VERSION 5.7 ;
  DIVIDERCHAR "/" ;
  BUSBITCHARS "[]" ;
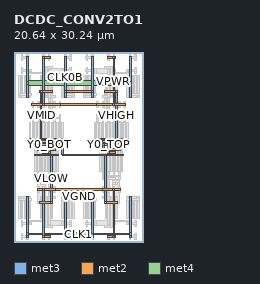
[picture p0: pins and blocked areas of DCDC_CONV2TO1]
MACRO DCDC_CONV2TO1
  CLASS BLOCK ;
  ORIGIN 0 0 ;
  FOREIGN DCDC_CONV2TO1 0 0 ;
  SIZE 20.64 BY 30.24 ;
  PIN CLK0
    DIRECTION INOUT ;
    USE SIGNAL ;
    PORT
      LAYER met3 ;
        RECT 18.35 0.68 18.63 7.3 ;
      LAYER met3 ;
        RECT 2.01 0.68 2.29 7.3 ;
      LAYER met3 ;
        RECT 18.35 1.075 18.63 1.445 ;
      LAYER met2 ;
        RECT 2.15 1.12 18.49 1.4 ;
      LAYER met3 ;
        RECT 2.01 1.075 2.29 1.445 ;
    END
  END CLK0
  PIN CLK0B
    DIRECTION INOUT ;
    USE SIGNAL ;
    PORT
      LAYER met3 ;
        RECT 12.33 22.94 12.61 29.56 ;
      LAYER met3 ;
        RECT 8.03 22.94 8.31 29.56 ;
      LAYER met3 ;
        RECT 12.33 23.755 12.61 24.125 ;
      LAYER met2 ;
        RECT 8.17 23.8 12.47 24.08 ;
      LAYER met3 ;
        RECT 8.03 23.755 8.31 24.125 ;
    END
  END CLK0B
  PIN CLK1
    DIRECTION INOUT ;
    USE SIGNAL ;
    PORT
      LAYER met3 ;
        RECT 12.33 0.68 12.61 7.3 ;
      LAYER met3 ;
        RECT 8.03 0.68 8.31 7.3 ;
      LAYER met3 ;
        RECT 12.33 0.915 12.61 1.285 ;
      LAYER met4 ;
        RECT 8.17 0.7 12.47 1.5 ;
      LAYER met3 ;
        RECT 8.03 0.915 8.31 1.285 ;
    END
  END CLK1
  PIN CLK1B
    DIRECTION INOUT ;
    USE SIGNAL ;
    PORT
      LAYER met3 ;
        RECT 18.35 22.94 18.63 29.56 ;
      LAYER met3 ;
        RECT 2.01 22.94 2.29 29.56 ;
      LAYER met3 ;
        RECT 18.35 25.115 18.63 25.485 ;
      LAYER met4 ;
        RECT 2.15 24.9 18.49 25.7 ;
      LAYER met3 ;
        RECT 2.01 25.115 2.29 25.485 ;
    END
  END CLK1B
  PIN VGND
    DIRECTION INOUT ;
    USE SIGNAL ;
    PORT
      LAYER met2 ;
        RECT 14.88 0.7 16.08 0.98 ;
      LAYER met2 ;
        RECT 14.02 8.26 16.94 8.54 ;
      LAYER met2 ;
        RECT 15.75 0.7 16.07 0.98 ;
      LAYER met3 ;
        RECT 15.77 0.84 16.05 8.4 ;
      LAYER met2 ;
        RECT 15.75 8.26 16.07 8.54 ;
      LAYER met2 ;
        RECT 4.56 0.7 5.76 0.98 ;
      LAYER met2 ;
        RECT 3.7 8.26 6.62 8.54 ;
      LAYER met2 ;
        RECT 4.57 0.7 4.89 0.98 ;
      LAYER met3 ;
        RECT 4.59 0.84 4.87 8.4 ;
      LAYER met2 ;
        RECT 4.57 8.26 4.89 8.54 ;
      LAYER met2 ;
        RECT 6.45 8.26 14.19 8.54 ;
    END
  END VGND
  PIN VHIGH
    DIRECTION INOUT ;
    USE SIGNAL ;
    PORT
      LAYER met2 ;
        RECT 14.45 23.8 16.51 24.08 ;
      LAYER met2 ;
        RECT 12.73 16.24 18.23 16.52 ;
      LAYER met2 ;
        RECT 16.18 23.8 16.5 24.08 ;
      LAYER met3 ;
        RECT 16.2 16.38 16.48 23.94 ;
      LAYER met2 ;
        RECT 16.18 16.24 16.5 16.52 ;
    END
  END VHIGH
  PIN VLOW
    DIRECTION INOUT ;
    USE SIGNAL ;
    PORT
      LAYER met2 ;
        RECT 4.13 6.16 6.19 6.44 ;
      LAYER met2 ;
        RECT 3.27 13.72 7.05 14 ;
      LAYER met2 ;
        RECT 5.86 6.16 6.18 6.44 ;
      LAYER met3 ;
        RECT 5.88 6.3 6.16 13.86 ;
      LAYER met2 ;
        RECT 5.86 13.72 6.18 14 ;
    END
  END VLOW
  PIN VMID
    DIRECTION INOUT ;
    USE SIGNAL ;
    PORT
      LAYER met2 ;
        RECT 14.45 6.16 16.51 6.44 ;
      LAYER met2 ;
        RECT 13.59 13.72 17.37 14 ;
      LAYER met2 ;
        RECT 14.46 6.16 14.78 6.44 ;
      LAYER met3 ;
        RECT 14.48 6.3 14.76 13.86 ;
      LAYER met2 ;
        RECT 14.46 13.72 14.78 14 ;
      LAYER met2 ;
        RECT 4.13 23.8 6.19 24.08 ;
      LAYER met2 ;
        RECT 2.41 16.24 7.91 16.52 ;
      LAYER met2 ;
        RECT 4.14 23.8 4.46 24.08 ;
      LAYER met3 ;
        RECT 4.16 16.38 4.44 23.94 ;
      LAYER met2 ;
        RECT 4.14 16.24 4.46 16.52 ;
      LAYER met2 ;
        RECT 7.74 13.72 13.76 14 ;
      LAYER met3 ;
        RECT 7.6 13.86 7.88 16.38 ;
      LAYER met2 ;
        RECT 7.58 16.24 7.9 16.52 ;
    END
  END VMID
  PIN VPWR
    DIRECTION INOUT ;
    USE SIGNAL ;
    PORT
      LAYER met2 ;
        RECT 14.88 29.26 16.08 29.54 ;
      LAYER met2 ;
        RECT 13.16 21.7 17.8 21.98 ;
      LAYER met2 ;
        RECT 15.75 29.26 16.07 29.54 ;
      LAYER met3 ;
        RECT 15.77 21.84 16.05 29.4 ;
      LAYER met2 ;
        RECT 15.75 21.7 16.07 21.98 ;
      LAYER met2 ;
        RECT 4.56 29.26 5.76 29.54 ;
      LAYER met2 ;
        RECT 2.84 21.7 7.48 21.98 ;
      LAYER met2 ;
        RECT 4.57 29.26 4.89 29.54 ;
      LAYER met3 ;
        RECT 4.59 21.84 4.87 29.4 ;
      LAYER met2 ;
        RECT 4.57 21.7 4.89 21.98 ;
      LAYER met2 ;
        RECT 7.31 21.7 13.33 21.98 ;
    END
  END VPWR
  PIN Y0_BOT
    DIRECTION INOUT ;
    USE SIGNAL ;
    PORT
      LAYER met2 ;
        RECT 3.7 15.4 7.48 15.68 ;
      LAYER met2 ;
        RECT 3.7 14.56 6.62 14.84 ;
      LAYER met2 ;
        RECT 6.29 15.4 6.61 15.68 ;
      LAYER met3 ;
        RECT 6.31 14.7 6.59 15.54 ;
      LAYER met2 ;
        RECT 6.29 14.56 6.61 14.84 ;
    END
  END Y0_BOT
  PIN Y0_TOP
    DIRECTION INOUT ;
    USE SIGNAL ;
    PORT
      LAYER met2 ;
        RECT 13.16 15.4 16.94 15.68 ;
      LAYER met2 ;
        RECT 14.02 14.56 16.94 14.84 ;
      LAYER met2 ;
        RECT 14.03 15.4 14.35 15.68 ;
      LAYER met3 ;
        RECT 14.05 14.7 14.33 15.54 ;
      LAYER met2 ;
        RECT 14.03 14.56 14.35 14.84 ;
    END
  END Y0_TOP
  PIN Y1_BOT
    DIRECTION INOUT ;
    USE SIGNAL ;
    PORT
      LAYER met2 ;
        RECT 2.84 15.82 6.62 16.1 ;
      LAYER met2 ;
        RECT 4.56 14.14 5.76 14.42 ;
      LAYER met2 ;
        RECT 5.43 15.82 5.75 16.1 ;
      LAYER met3 ;
        RECT 5.45 14.28 5.73 15.96 ;
      LAYER met2 ;
        RECT 5.43 14.14 5.75 14.42 ;
    END
  END Y1_BOT
  PIN Y1_TOP
    DIRECTION INOUT ;
    USE SIGNAL ;
    PORT
      LAYER met2 ;
        RECT 14.02 15.82 17.8 16.1 ;
      LAYER met2 ;
        RECT 14.88 14.14 16.08 14.42 ;
      LAYER met2 ;
        RECT 14.89 15.82 15.21 16.1 ;
      LAYER met3 ;
        RECT 14.91 14.28 15.19 15.96 ;
      LAYER met2 ;
        RECT 14.89 14.14 15.21 14.42 ;
    END
  END Y1_TOP
  OBS
  LAYER met3 ;
        RECT 14.91 22.94 15.19 27.46 ;
  LAYER met2 ;
        RECT 13.16 19.6 16.94 19.88 ;
  LAYER met2 ;
        RECT 11.44 27.16 12.64 27.44 ;
  LAYER met3 ;
        RECT 14.91 19.74 15.19 23.1 ;
  LAYER met2 ;
        RECT 14.89 19.6 15.21 19.88 ;
  LAYER met3 ;
        RECT 14.91 27.035 15.19 27.405 ;
  LAYER met4 ;
        RECT 12.9 26.82 15.05 27.62 ;
  LAYER met3 ;
        RECT 12.76 27.139 13.04 27.381 ;
  LAYER met2 ;
        RECT 12.47 27.16 12.9 27.44 ;
  LAYER met2 ;
        RECT 14.89 19.6 15.21 19.88 ;
  LAYER met3 ;
        RECT 14.91 19.58 15.19 19.9 ;
  LAYER met2 ;
        RECT 12.74 27.16 13.06 27.44 ;
  LAYER met3 ;
        RECT 12.76 27.14 13.04 27.46 ;
  LAYER met2 ;
        RECT 14.89 19.6 15.21 19.88 ;
  LAYER met3 ;
        RECT 14.91 19.58 15.19 19.9 ;
  LAYER met3 ;
        RECT 12.76 27.035 13.04 27.405 ;
  LAYER met4 ;
        RECT 12.735 26.82 13.065 27.62 ;
  LAYER met3 ;
        RECT 14.91 27.035 15.19 27.405 ;
  LAYER met4 ;
        RECT 14.885 26.82 15.215 27.62 ;
  LAYER met2 ;
        RECT 14.89 19.6 15.21 19.88 ;
  LAYER met3 ;
        RECT 14.91 19.58 15.19 19.9 ;
  LAYER met3 ;
        RECT 14.91 27.035 15.19 27.405 ;
  LAYER met4 ;
        RECT 14.885 26.82 15.215 27.62 ;
  LAYER met3 ;
        RECT 15.34 23.36 15.62 27.88 ;
  LAYER met2 ;
        RECT 14.02 20.02 17.8 20.3 ;
  LAYER met2 ;
        RECT 18.32 27.16 19.52 27.44 ;
  LAYER met3 ;
        RECT 15.34 23.735 15.62 24.105 ;
  LAYER met4 ;
        RECT 14.62 23.52 15.48 24.32 ;
  LAYER met3 ;
        RECT 14.48 20.16 14.76 23.92 ;
  LAYER met2 ;
        RECT 14.46 20.02 14.78 20.3 ;
  LAYER met3 ;
        RECT 15.34 26.695 15.62 27.065 ;
  LAYER met2 ;
        RECT 15.48 26.74 18.06 27.02 ;
  LAYER met1 ;
        RECT 17.935 26.88 18.185 27.3 ;
  LAYER met2 ;
        RECT 18.06 27.16 18.49 27.44 ;
  LAYER met2 ;
        RECT 14.46 20.02 14.78 20.3 ;
  LAYER met3 ;
        RECT 14.48 20 14.76 20.32 ;
  LAYER met3 ;
        RECT 14.48 23.735 14.76 24.105 ;
  LAYER met4 ;
        RECT 14.455 23.52 14.785 24.32 ;
  LAYER met3 ;
        RECT 15.34 23.735 15.62 24.105 ;
  LAYER met4 ;
        RECT 15.315 23.52 15.645 24.32 ;
  LAYER met1 ;
        RECT 17.935 26.795 18.185 26.965 ;
  LAYER met2 ;
        RECT 17.89 26.74 18.23 27.02 ;
  LAYER met1 ;
        RECT 17.935 27.215 18.185 27.385 ;
  LAYER met2 ;
        RECT 17.89 27.16 18.23 27.44 ;
  LAYER met2 ;
        RECT 14.46 20.02 14.78 20.3 ;
  LAYER met3 ;
        RECT 14.48 20 14.76 20.32 ;
  LAYER met2 ;
        RECT 15.32 26.74 15.64 27.02 ;
  LAYER met3 ;
        RECT 15.34 26.72 15.62 27.04 ;
  LAYER met3 ;
        RECT 14.48 23.735 14.76 24.105 ;
  LAYER met4 ;
        RECT 14.455 23.52 14.785 24.32 ;
  LAYER met3 ;
        RECT 15.34 23.735 15.62 24.105 ;
  LAYER met4 ;
        RECT 15.315 23.52 15.645 24.32 ;
  LAYER met1 ;
        RECT 17.935 26.795 18.185 26.965 ;
  LAYER met2 ;
        RECT 17.89 26.74 18.23 27.02 ;
  LAYER met1 ;
        RECT 17.935 27.215 18.185 27.385 ;
  LAYER met2 ;
        RECT 17.89 27.16 18.23 27.44 ;
  LAYER met2 ;
        RECT 14.46 20.02 14.78 20.3 ;
  LAYER met3 ;
        RECT 14.48 20 14.76 20.32 ;
  LAYER met2 ;
        RECT 15.32 26.74 15.64 27.02 ;
  LAYER met3 ;
        RECT 15.34 26.72 15.62 27.04 ;
  LAYER met3 ;
        RECT 14.48 23.735 14.76 24.105 ;
  LAYER met4 ;
        RECT 14.455 23.52 14.785 24.32 ;
  LAYER met3 ;
        RECT 15.34 23.735 15.62 24.105 ;
  LAYER met4 ;
        RECT 15.315 23.52 15.645 24.32 ;
  LAYER met1 ;
        RECT 14.925 23.015 15.175 26.545 ;
  LAYER met1 ;
        RECT 14.925 26.795 15.175 27.805 ;
  LAYER met1 ;
        RECT 14.925 28.895 15.175 29.905 ;
  LAYER met1 ;
        RECT 14.495 23.015 14.745 26.545 ;
  LAYER met1 ;
        RECT 15.355 23.015 15.605 26.545 ;
  LAYER met1 ;
        RECT 15.785 23.015 16.035 26.545 ;
  LAYER met1 ;
        RECT 15.785 26.795 16.035 27.805 ;
  LAYER met1 ;
        RECT 15.785 28.895 16.035 29.905 ;
  LAYER met1 ;
        RECT 16.215 23.015 16.465 26.545 ;
  LAYER met2 ;
        RECT 14.88 27.16 16.08 27.44 ;
  LAYER met2 ;
        RECT 14.02 22.96 15.22 23.24 ;
  LAYER met2 ;
        RECT 14.45 27.58 15.65 27.86 ;
  LAYER met2 ;
        RECT 14.88 23.38 16.08 23.66 ;
  LAYER met2 ;
        RECT 14.88 29.26 16.08 29.54 ;
  LAYER met3 ;
        RECT 14.91 22.94 15.19 27.46 ;
  LAYER met3 ;
        RECT 15.34 23.36 15.62 27.88 ;
  LAYER met2 ;
        RECT 14.45 23.8 16.51 24.08 ;
  LAYER met1 ;
        RECT 13.205 15.455 13.455 18.985 ;
  LAYER met1 ;
        RECT 13.205 19.235 13.455 20.245 ;
  LAYER met1 ;
        RECT 13.205 21.335 13.455 22.345 ;
  LAYER met1 ;
        RECT 12.775 15.455 13.025 18.985 ;
  LAYER met1 ;
        RECT 13.635 15.455 13.885 18.985 ;
  LAYER met1 ;
        RECT 14.065 15.455 14.315 18.985 ;
  LAYER met1 ;
        RECT 14.065 19.235 14.315 20.245 ;
  LAYER met1 ;
        RECT 14.065 21.335 14.315 22.345 ;
  LAYER met1 ;
        RECT 14.495 15.455 14.745 18.985 ;
  LAYER met1 ;
        RECT 14.925 15.455 15.175 18.985 ;
  LAYER met1 ;
        RECT 14.925 19.235 15.175 20.245 ;
  LAYER met1 ;
        RECT 14.925 21.335 15.175 22.345 ;
  LAYER met1 ;
        RECT 15.355 15.455 15.605 18.985 ;
  LAYER met1 ;
        RECT 15.785 15.455 16.035 18.985 ;
  LAYER met1 ;
        RECT 15.785 19.235 16.035 20.245 ;
  LAYER met1 ;
        RECT 15.785 21.335 16.035 22.345 ;
  LAYER met1 ;
        RECT 16.215 15.455 16.465 18.985 ;
  LAYER met1 ;
        RECT 16.645 15.455 16.895 18.985 ;
  LAYER met1 ;
        RECT 16.645 19.235 16.895 20.245 ;
  LAYER met1 ;
        RECT 16.645 21.335 16.895 22.345 ;
  LAYER met1 ;
        RECT 17.075 15.455 17.325 18.985 ;
  LAYER met1 ;
        RECT 17.505 15.455 17.755 18.985 ;
  LAYER met1 ;
        RECT 17.505 19.235 17.755 20.245 ;
  LAYER met1 ;
        RECT 17.505 21.335 17.755 22.345 ;
  LAYER met1 ;
        RECT 17.935 15.455 18.185 18.985 ;
  LAYER met2 ;
        RECT 13.16 21.7 17.8 21.98 ;
  LAYER met2 ;
        RECT 13.16 15.4 16.94 15.68 ;
  LAYER met2 ;
        RECT 14.02 15.82 17.8 16.1 ;
  LAYER met2 ;
        RECT 13.16 19.6 16.94 19.88 ;
  LAYER met2 ;
        RECT 14.02 20.02 17.8 20.3 ;
  LAYER met2 ;
        RECT 12.73 16.24 18.23 16.52 ;
  LAYER met1 ;
        RECT 11.485 23.015 11.735 26.545 ;
  LAYER met1 ;
        RECT 11.485 26.795 11.735 27.805 ;
  LAYER met1 ;
        RECT 11.485 28.895 11.735 29.905 ;
  LAYER met1 ;
        RECT 11.055 23.015 11.305 26.545 ;
  LAYER met1 ;
        RECT 11.915 23.015 12.165 26.545 ;
  LAYER met1 ;
        RECT 12.345 23.015 12.595 26.545 ;
  LAYER met1 ;
        RECT 12.345 26.795 12.595 27.805 ;
  LAYER met1 ;
        RECT 12.345 28.895 12.595 29.905 ;
  LAYER met1 ;
        RECT 12.775 23.015 13.025 26.545 ;
  LAYER met2 ;
        RECT 11.44 29.26 12.64 29.54 ;
  LAYER met2 ;
        RECT 11.44 22.96 12.64 23.24 ;
  LAYER met2 ;
        RECT 11.01 23.38 13.07 23.66 ;
  LAYER met2 ;
        RECT 11.44 27.16 12.64 27.44 ;
  LAYER met3 ;
        RECT 12.33 22.94 12.61 29.56 ;
  LAYER met1 ;
        RECT 19.225 23.015 19.475 26.545 ;
  LAYER met1 ;
        RECT 19.225 26.795 19.475 27.805 ;
  LAYER met1 ;
        RECT 19.225 28.895 19.475 29.905 ;
  LAYER met1 ;
        RECT 19.655 23.015 19.905 26.545 ;
  LAYER met1 ;
        RECT 18.795 23.015 19.045 26.545 ;
  LAYER met1 ;
        RECT 18.365 23.015 18.615 26.545 ;
  LAYER met1 ;
        RECT 18.365 26.795 18.615 27.805 ;
  LAYER met1 ;
        RECT 18.365 28.895 18.615 29.905 ;
  LAYER met1 ;
        RECT 17.935 23.015 18.185 26.545 ;
  LAYER met2 ;
        RECT 18.32 29.26 19.52 29.54 ;
  LAYER met2 ;
        RECT 18.32 22.96 19.52 23.24 ;
  LAYER met2 ;
        RECT 17.89 23.38 19.95 23.66 ;
  LAYER met2 ;
        RECT 18.32 27.16 19.52 27.44 ;
  LAYER met3 ;
        RECT 18.35 22.94 18.63 29.56 ;
  LAYER met3 ;
        RECT 14.91 2.78 15.19 7.3 ;
  LAYER met2 ;
        RECT 14.02 10.36 16.94 10.64 ;
  LAYER met2 ;
        RECT 11.44 2.8 12.64 3.08 ;
  LAYER met3 ;
        RECT 14.91 7.14 15.19 10.5 ;
  LAYER met2 ;
        RECT 14.89 10.36 15.21 10.64 ;
  LAYER met3 ;
        RECT 14.91 2.835 15.19 3.205 ;
  LAYER met4 ;
        RECT 12.9 2.62 15.05 3.42 ;
  LAYER met3 ;
        RECT 12.76 2.859 13.04 3.101 ;
  LAYER met2 ;
        RECT 12.47 2.8 12.9 3.08 ;
  LAYER met2 ;
        RECT 14.89 10.36 15.21 10.64 ;
  LAYER met3 ;
        RECT 14.91 10.34 15.19 10.66 ;
  LAYER met2 ;
        RECT 12.74 2.8 13.06 3.08 ;
  LAYER met3 ;
        RECT 12.76 2.78 13.04 3.1 ;
  LAYER met2 ;
        RECT 14.89 10.36 15.21 10.64 ;
  LAYER met3 ;
        RECT 14.91 10.34 15.19 10.66 ;
  LAYER met3 ;
        RECT 12.76 2.835 13.04 3.205 ;
  LAYER met4 ;
        RECT 12.735 2.62 13.065 3.42 ;
  LAYER met3 ;
        RECT 14.91 2.835 15.19 3.205 ;
  LAYER met4 ;
        RECT 14.885 2.62 15.215 3.42 ;
  LAYER met2 ;
        RECT 14.89 10.36 15.21 10.64 ;
  LAYER met3 ;
        RECT 14.91 10.34 15.19 10.66 ;
  LAYER met3 ;
        RECT 14.91 2.835 15.19 3.205 ;
  LAYER met4 ;
        RECT 14.885 2.62 15.215 3.42 ;
  LAYER met3 ;
        RECT 15.34 2.36 15.62 6.88 ;
  LAYER met2 ;
        RECT 14.88 9.94 16.08 10.22 ;
  LAYER met2 ;
        RECT 18.32 2.8 19.52 3.08 ;
  LAYER met3 ;
        RECT 15.34 6.135 15.62 6.505 ;
  LAYER met4 ;
        RECT 15.48 5.92 16.24 6.72 ;
  LAYER met5 ;
        RECT 15.65 6.32 16.83 9.62 ;
  LAYER met4 ;
        RECT 15.91 9.22 16.24 10.02 ;
  LAYER met3 ;
        RECT 15.77 9.62 16.05 10.08 ;
  LAYER met2 ;
        RECT 15.75 9.94 16.07 10.22 ;
  LAYER met3 ;
        RECT 15.34 3.175 15.62 3.545 ;
  LAYER met2 ;
        RECT 15.48 3.22 18.06 3.5 ;
  LAYER met1 ;
        RECT 17.935 2.94 18.185 3.36 ;
  LAYER met2 ;
        RECT 18.06 2.8 18.49 3.08 ;
  LAYER met2 ;
        RECT 15.75 9.94 16.07 10.22 ;
  LAYER met3 ;
        RECT 15.77 9.92 16.05 10.24 ;
  LAYER met3 ;
        RECT 15.34 6.135 15.62 6.505 ;
  LAYER met4 ;
        RECT 15.315 5.92 15.645 6.72 ;
  LAYER met3 ;
        RECT 15.77 9.435 16.05 9.805 ;
  LAYER met4 ;
        RECT 15.745 9.22 16.075 10.02 ;
  LAYER met4 ;
        RECT 16.075 9.22 16.405 10.02 ;
  LAYER met5 ;
        RECT 15.65 9.455 16.83 9.785 ;
  LAYER met4 ;
        RECT 16.075 5.92 16.405 6.72 ;
  LAYER met5 ;
        RECT 15.65 6.155 16.83 6.485 ;
  LAYER met1 ;
        RECT 17.935 3.275 18.185 3.445 ;
  LAYER met2 ;
        RECT 17.89 3.22 18.23 3.5 ;
  LAYER met1 ;
        RECT 17.935 2.855 18.185 3.025 ;
  LAYER met2 ;
        RECT 17.89 2.8 18.23 3.08 ;
  LAYER met2 ;
        RECT 15.32 3.22 15.64 3.5 ;
  LAYER met3 ;
        RECT 15.34 3.2 15.62 3.52 ;
  LAYER met2 ;
        RECT 15.75 9.94 16.07 10.22 ;
  LAYER met3 ;
        RECT 15.77 9.92 16.05 10.24 ;
  LAYER met3 ;
        RECT 15.34 6.135 15.62 6.505 ;
  LAYER met4 ;
        RECT 15.315 5.92 15.645 6.72 ;
  LAYER met3 ;
        RECT 15.77 9.435 16.05 9.805 ;
  LAYER met4 ;
        RECT 15.745 9.22 16.075 10.02 ;
  LAYER met4 ;
        RECT 16.075 9.22 16.405 10.02 ;
  LAYER met5 ;
        RECT 15.65 9.455 16.83 9.785 ;
  LAYER met4 ;
        RECT 16.075 5.92 16.405 6.72 ;
  LAYER met5 ;
        RECT 15.65 6.155 16.83 6.485 ;
  LAYER met1 ;
        RECT 17.935 3.275 18.185 3.445 ;
  LAYER met2 ;
        RECT 17.89 3.22 18.23 3.5 ;
  LAYER met1 ;
        RECT 17.935 2.855 18.185 3.025 ;
  LAYER met2 ;
        RECT 17.89 2.8 18.23 3.08 ;
  LAYER met2 ;
        RECT 15.32 3.22 15.64 3.5 ;
  LAYER met3 ;
        RECT 15.34 3.2 15.62 3.52 ;
  LAYER met2 ;
        RECT 15.75 9.94 16.07 10.22 ;
  LAYER met3 ;
        RECT 15.77 9.92 16.05 10.24 ;
  LAYER met3 ;
        RECT 15.34 6.135 15.62 6.505 ;
  LAYER met4 ;
        RECT 15.315 5.92 15.645 6.72 ;
  LAYER met3 ;
        RECT 15.77 9.435 16.05 9.805 ;
  LAYER met4 ;
        RECT 15.745 9.22 16.075 10.02 ;
  LAYER met4 ;
        RECT 16.075 9.22 16.405 10.02 ;
  LAYER met5 ;
        RECT 15.65 9.455 16.83 9.785 ;
  LAYER met4 ;
        RECT 16.075 5.92 16.405 6.72 ;
  LAYER met5 ;
        RECT 15.65 6.155 16.83 6.485 ;
  LAYER met1 ;
        RECT 14.925 3.695 15.175 7.225 ;
  LAYER met1 ;
        RECT 14.925 2.435 15.175 3.445 ;
  LAYER met1 ;
        RECT 14.925 0.335 15.175 1.345 ;
  LAYER met1 ;
        RECT 14.495 3.695 14.745 7.225 ;
  LAYER met1 ;
        RECT 15.355 3.695 15.605 7.225 ;
  LAYER met1 ;
        RECT 15.785 3.695 16.035 7.225 ;
  LAYER met1 ;
        RECT 15.785 2.435 16.035 3.445 ;
  LAYER met1 ;
        RECT 15.785 0.335 16.035 1.345 ;
  LAYER met1 ;
        RECT 16.215 3.695 16.465 7.225 ;
  LAYER met2 ;
        RECT 14.88 2.8 16.08 3.08 ;
  LAYER met2 ;
        RECT 14.02 7 15.22 7.28 ;
  LAYER met2 ;
        RECT 14.45 2.38 15.65 2.66 ;
  LAYER met2 ;
        RECT 14.88 6.58 16.08 6.86 ;
  LAYER met2 ;
        RECT 14.88 0.7 16.08 0.98 ;
  LAYER met3 ;
        RECT 14.91 2.78 15.19 7.3 ;
  LAYER met3 ;
        RECT 15.34 2.36 15.62 6.88 ;
  LAYER met2 ;
        RECT 14.45 6.16 16.51 6.44 ;
  LAYER met1 ;
        RECT 14.065 11.255 14.315 14.785 ;
  LAYER met1 ;
        RECT 14.065 9.995 14.315 11.005 ;
  LAYER met1 ;
        RECT 14.065 7.895 14.315 8.905 ;
  LAYER met1 ;
        RECT 13.635 11.255 13.885 14.785 ;
  LAYER met1 ;
        RECT 14.495 11.255 14.745 14.785 ;
  LAYER met1 ;
        RECT 14.925 11.255 15.175 14.785 ;
  LAYER met1 ;
        RECT 14.925 9.995 15.175 11.005 ;
  LAYER met1 ;
        RECT 14.925 7.895 15.175 8.905 ;
  LAYER met1 ;
        RECT 15.355 11.255 15.605 14.785 ;
  LAYER met1 ;
        RECT 15.785 11.255 16.035 14.785 ;
  LAYER met1 ;
        RECT 15.785 9.995 16.035 11.005 ;
  LAYER met1 ;
        RECT 15.785 7.895 16.035 8.905 ;
  LAYER met1 ;
        RECT 16.215 11.255 16.465 14.785 ;
  LAYER met1 ;
        RECT 16.645 11.255 16.895 14.785 ;
  LAYER met1 ;
        RECT 16.645 9.995 16.895 11.005 ;
  LAYER met1 ;
        RECT 16.645 7.895 16.895 8.905 ;
  LAYER met1 ;
        RECT 17.075 11.255 17.325 14.785 ;
  LAYER met2 ;
        RECT 14.02 8.26 16.94 8.54 ;
  LAYER met2 ;
        RECT 14.02 14.56 16.94 14.84 ;
  LAYER met2 ;
        RECT 14.88 14.14 16.08 14.42 ;
  LAYER met2 ;
        RECT 14.02 10.36 16.94 10.64 ;
  LAYER met2 ;
        RECT 14.88 9.94 16.08 10.22 ;
  LAYER met2 ;
        RECT 13.59 13.72 17.37 14 ;
  LAYER met1 ;
        RECT 11.485 3.695 11.735 7.225 ;
  LAYER met1 ;
        RECT 11.485 2.435 11.735 3.445 ;
  LAYER met1 ;
        RECT 11.485 0.335 11.735 1.345 ;
  LAYER met1 ;
        RECT 11.055 3.695 11.305 7.225 ;
  LAYER met1 ;
        RECT 11.915 3.695 12.165 7.225 ;
  LAYER met1 ;
        RECT 12.345 3.695 12.595 7.225 ;
  LAYER met1 ;
        RECT 12.345 2.435 12.595 3.445 ;
  LAYER met1 ;
        RECT 12.345 0.335 12.595 1.345 ;
  LAYER met1 ;
        RECT 12.775 3.695 13.025 7.225 ;
  LAYER met2 ;
        RECT 11.44 0.7 12.64 0.98 ;
  LAYER met2 ;
        RECT 11.44 7 12.64 7.28 ;
  LAYER met2 ;
        RECT 11.01 6.58 13.07 6.86 ;
  LAYER met2 ;
        RECT 11.44 2.8 12.64 3.08 ;
  LAYER met3 ;
        RECT 12.33 0.68 12.61 7.3 ;
  LAYER met1 ;
        RECT 19.225 3.695 19.475 7.225 ;
  LAYER met1 ;
        RECT 19.225 2.435 19.475 3.445 ;
  LAYER met1 ;
        RECT 19.225 0.335 19.475 1.345 ;
  LAYER met1 ;
        RECT 19.655 3.695 19.905 7.225 ;
  LAYER met1 ;
        RECT 18.795 3.695 19.045 7.225 ;
  LAYER met1 ;
        RECT 18.365 3.695 18.615 7.225 ;
  LAYER met1 ;
        RECT 18.365 2.435 18.615 3.445 ;
  LAYER met1 ;
        RECT 18.365 0.335 18.615 1.345 ;
  LAYER met1 ;
        RECT 17.935 3.695 18.185 7.225 ;
  LAYER met2 ;
        RECT 18.32 0.7 19.52 0.98 ;
  LAYER met2 ;
        RECT 18.32 7 19.52 7.28 ;
  LAYER met2 ;
        RECT 17.89 6.58 19.95 6.86 ;
  LAYER met2 ;
        RECT 18.32 2.8 19.52 3.08 ;
  LAYER met3 ;
        RECT 18.35 0.68 18.63 7.3 ;
  LAYER met3 ;
        RECT 5.45 22.94 5.73 27.46 ;
  LAYER met2 ;
        RECT 3.7 19.6 7.48 19.88 ;
  LAYER met2 ;
        RECT 8 27.16 9.2 27.44 ;
  LAYER met3 ;
        RECT 5.45 19.74 5.73 23.1 ;
  LAYER met2 ;
        RECT 5.43 19.6 5.75 19.88 ;
  LAYER met3 ;
        RECT 5.45 27.035 5.73 27.405 ;
  LAYER met4 ;
        RECT 5.59 26.82 7.74 27.62 ;
  LAYER met3 ;
        RECT 7.6 27.139 7.88 27.381 ;
  LAYER met2 ;
        RECT 7.74 27.16 8.17 27.44 ;
  LAYER met2 ;
        RECT 5.43 19.6 5.75 19.88 ;
  LAYER met3 ;
        RECT 5.45 19.58 5.73 19.9 ;
  LAYER met2 ;
        RECT 7.58 27.16 7.9 27.44 ;
  LAYER met3 ;
        RECT 7.6 27.14 7.88 27.46 ;
  LAYER met2 ;
        RECT 5.43 19.6 5.75 19.88 ;
  LAYER met3 ;
        RECT 5.45 19.58 5.73 19.9 ;
  LAYER met3 ;
        RECT 7.6 27.035 7.88 27.405 ;
  LAYER met4 ;
        RECT 7.575 26.82 7.905 27.62 ;
  LAYER met3 ;
        RECT 5.45 27.035 5.73 27.405 ;
  LAYER met4 ;
        RECT 5.425 26.82 5.755 27.62 ;
  LAYER met2 ;
        RECT 5.43 19.6 5.75 19.88 ;
  LAYER met3 ;
        RECT 5.45 19.58 5.73 19.9 ;
  LAYER met3 ;
        RECT 5.45 27.035 5.73 27.405 ;
  LAYER met4 ;
        RECT 5.425 26.82 5.755 27.62 ;
  LAYER met3 ;
        RECT 5.02 23.36 5.3 27.88 ;
  LAYER met2 ;
        RECT 2.84 20.02 6.62 20.3 ;
  LAYER met2 ;
        RECT 1.12 27.16 2.32 27.44 ;
  LAYER met3 ;
        RECT 5.02 23.735 5.3 24.105 ;
  LAYER met4 ;
        RECT 5.16 23.52 6.02 24.32 ;
  LAYER met3 ;
        RECT 5.88 20.16 6.16 23.92 ;
  LAYER met2 ;
        RECT 5.86 20.02 6.18 20.3 ;
  LAYER met3 ;
        RECT 5.02 26.695 5.3 27.065 ;
  LAYER met2 ;
        RECT 2.58 26.74 5.16 27.02 ;
  LAYER met1 ;
        RECT 2.455 26.88 2.705 27.3 ;
  LAYER met2 ;
        RECT 2.15 27.16 2.58 27.44 ;
  LAYER met2 ;
        RECT 5.86 20.02 6.18 20.3 ;
  LAYER met3 ;
        RECT 5.88 20 6.16 20.32 ;
  LAYER met3 ;
        RECT 5.88 23.735 6.16 24.105 ;
  LAYER met4 ;
        RECT 5.855 23.52 6.185 24.32 ;
  LAYER met3 ;
        RECT 5.02 23.735 5.3 24.105 ;
  LAYER met4 ;
        RECT 4.995 23.52 5.325 24.32 ;
  LAYER met1 ;
        RECT 2.455 26.795 2.705 26.965 ;
  LAYER met2 ;
        RECT 2.41 26.74 2.75 27.02 ;
  LAYER met1 ;
        RECT 2.455 27.215 2.705 27.385 ;
  LAYER met2 ;
        RECT 2.41 27.16 2.75 27.44 ;
  LAYER met2 ;
        RECT 5.86 20.02 6.18 20.3 ;
  LAYER met3 ;
        RECT 5.88 20 6.16 20.32 ;
  LAYER met2 ;
        RECT 5 26.74 5.32 27.02 ;
  LAYER met3 ;
        RECT 5.02 26.72 5.3 27.04 ;
  LAYER met3 ;
        RECT 5.88 23.735 6.16 24.105 ;
  LAYER met4 ;
        RECT 5.855 23.52 6.185 24.32 ;
  LAYER met3 ;
        RECT 5.02 23.735 5.3 24.105 ;
  LAYER met4 ;
        RECT 4.995 23.52 5.325 24.32 ;
  LAYER met1 ;
        RECT 2.455 26.795 2.705 26.965 ;
  LAYER met2 ;
        RECT 2.41 26.74 2.75 27.02 ;
  LAYER met1 ;
        RECT 2.455 27.215 2.705 27.385 ;
  LAYER met2 ;
        RECT 2.41 27.16 2.75 27.44 ;
  LAYER met2 ;
        RECT 5.86 20.02 6.18 20.3 ;
  LAYER met3 ;
        RECT 5.88 20 6.16 20.32 ;
  LAYER met2 ;
        RECT 5 26.74 5.32 27.02 ;
  LAYER met3 ;
        RECT 5.02 26.72 5.3 27.04 ;
  LAYER met3 ;
        RECT 5.88 23.735 6.16 24.105 ;
  LAYER met4 ;
        RECT 5.855 23.52 6.185 24.32 ;
  LAYER met3 ;
        RECT 5.02 23.735 5.3 24.105 ;
  LAYER met4 ;
        RECT 4.995 23.52 5.325 24.32 ;
  LAYER met1 ;
        RECT 5.465 23.015 5.715 26.545 ;
  LAYER met1 ;
        RECT 5.465 26.795 5.715 27.805 ;
  LAYER met1 ;
        RECT 5.465 28.895 5.715 29.905 ;
  LAYER met1 ;
        RECT 5.895 23.015 6.145 26.545 ;
  LAYER met1 ;
        RECT 5.035 23.015 5.285 26.545 ;
  LAYER met1 ;
        RECT 4.605 23.015 4.855 26.545 ;
  LAYER met1 ;
        RECT 4.605 26.795 4.855 27.805 ;
  LAYER met1 ;
        RECT 4.605 28.895 4.855 29.905 ;
  LAYER met1 ;
        RECT 4.175 23.015 4.425 26.545 ;
  LAYER met2 ;
        RECT 4.56 27.16 5.76 27.44 ;
  LAYER met2 ;
        RECT 5.42 22.96 6.62 23.24 ;
  LAYER met2 ;
        RECT 4.99 27.58 6.19 27.86 ;
  LAYER met2 ;
        RECT 4.56 23.38 5.76 23.66 ;
  LAYER met2 ;
        RECT 4.56 29.26 5.76 29.54 ;
  LAYER met3 ;
        RECT 5.45 22.94 5.73 27.46 ;
  LAYER met3 ;
        RECT 5.02 23.36 5.3 27.88 ;
  LAYER met2 ;
        RECT 4.13 23.8 6.19 24.08 ;
  LAYER met1 ;
        RECT 7.185 15.455 7.435 18.985 ;
  LAYER met1 ;
        RECT 7.185 19.235 7.435 20.245 ;
  LAYER met1 ;
        RECT 7.185 21.335 7.435 22.345 ;
  LAYER met1 ;
        RECT 7.615 15.455 7.865 18.985 ;
  LAYER met1 ;
        RECT 6.755 15.455 7.005 18.985 ;
  LAYER met1 ;
        RECT 6.325 15.455 6.575 18.985 ;
  LAYER met1 ;
        RECT 6.325 19.235 6.575 20.245 ;
  LAYER met1 ;
        RECT 6.325 21.335 6.575 22.345 ;
  LAYER met1 ;
        RECT 5.895 15.455 6.145 18.985 ;
  LAYER met1 ;
        RECT 5.465 15.455 5.715 18.985 ;
  LAYER met1 ;
        RECT 5.465 19.235 5.715 20.245 ;
  LAYER met1 ;
        RECT 5.465 21.335 5.715 22.345 ;
  LAYER met1 ;
        RECT 5.035 15.455 5.285 18.985 ;
  LAYER met1 ;
        RECT 4.605 15.455 4.855 18.985 ;
  LAYER met1 ;
        RECT 4.605 19.235 4.855 20.245 ;
  LAYER met1 ;
        RECT 4.605 21.335 4.855 22.345 ;
  LAYER met1 ;
        RECT 4.175 15.455 4.425 18.985 ;
  LAYER met1 ;
        RECT 3.745 15.455 3.995 18.985 ;
  LAYER met1 ;
        RECT 3.745 19.235 3.995 20.245 ;
  LAYER met1 ;
        RECT 3.745 21.335 3.995 22.345 ;
  LAYER met1 ;
        RECT 3.315 15.455 3.565 18.985 ;
  LAYER met1 ;
        RECT 2.885 15.455 3.135 18.985 ;
  LAYER met1 ;
        RECT 2.885 19.235 3.135 20.245 ;
  LAYER met1 ;
        RECT 2.885 21.335 3.135 22.345 ;
  LAYER met1 ;
        RECT 2.455 15.455 2.705 18.985 ;
  LAYER met2 ;
        RECT 2.84 21.7 7.48 21.98 ;
  LAYER met2 ;
        RECT 3.7 15.4 7.48 15.68 ;
  LAYER met2 ;
        RECT 2.84 15.82 6.62 16.1 ;
  LAYER met2 ;
        RECT 3.7 19.6 7.48 19.88 ;
  LAYER met2 ;
        RECT 2.84 20.02 6.62 20.3 ;
  LAYER met2 ;
        RECT 2.41 16.24 7.91 16.52 ;
  LAYER met1 ;
        RECT 8.905 23.015 9.155 26.545 ;
  LAYER met1 ;
        RECT 8.905 26.795 9.155 27.805 ;
  LAYER met1 ;
        RECT 8.905 28.895 9.155 29.905 ;
  LAYER met1 ;
        RECT 9.335 23.015 9.585 26.545 ;
  LAYER met1 ;
        RECT 8.475 23.015 8.725 26.545 ;
  LAYER met1 ;
        RECT 8.045 23.015 8.295 26.545 ;
  LAYER met1 ;
        RECT 8.045 26.795 8.295 27.805 ;
  LAYER met1 ;
        RECT 8.045 28.895 8.295 29.905 ;
  LAYER met1 ;
        RECT 7.615 23.015 7.865 26.545 ;
  LAYER met2 ;
        RECT 8 29.26 9.2 29.54 ;
  LAYER met2 ;
        RECT 8 22.96 9.2 23.24 ;
  LAYER met2 ;
        RECT 7.57 23.38 9.63 23.66 ;
  LAYER met2 ;
        RECT 8 27.16 9.2 27.44 ;
  LAYER met3 ;
        RECT 8.03 22.94 8.31 29.56 ;
  LAYER met1 ;
        RECT 1.165 23.015 1.415 26.545 ;
  LAYER met1 ;
        RECT 1.165 26.795 1.415 27.805 ;
  LAYER met1 ;
        RECT 1.165 28.895 1.415 29.905 ;
  LAYER met1 ;
        RECT 0.735 23.015 0.985 26.545 ;
  LAYER met1 ;
        RECT 1.595 23.015 1.845 26.545 ;
  LAYER met1 ;
        RECT 2.025 23.015 2.275 26.545 ;
  LAYER met1 ;
        RECT 2.025 26.795 2.275 27.805 ;
  LAYER met1 ;
        RECT 2.025 28.895 2.275 29.905 ;
  LAYER met1 ;
        RECT 2.455 23.015 2.705 26.545 ;
  LAYER met2 ;
        RECT 1.12 29.26 2.32 29.54 ;
  LAYER met2 ;
        RECT 1.12 22.96 2.32 23.24 ;
  LAYER met2 ;
        RECT 0.69 23.38 2.75 23.66 ;
  LAYER met2 ;
        RECT 1.12 27.16 2.32 27.44 ;
  LAYER met3 ;
        RECT 2.01 22.94 2.29 29.56 ;
  LAYER met3 ;
        RECT 5.45 2.78 5.73 7.3 ;
  LAYER met2 ;
        RECT 3.7 10.36 6.62 10.64 ;
  LAYER met2 ;
        RECT 8 2.8 9.2 3.08 ;
  LAYER met3 ;
        RECT 5.45 7.14 5.73 10.5 ;
  LAYER met2 ;
        RECT 5.43 10.36 5.75 10.64 ;
  LAYER met3 ;
        RECT 5.45 2.835 5.73 3.205 ;
  LAYER met4 ;
        RECT 5.59 2.62 7.74 3.42 ;
  LAYER met3 ;
        RECT 7.6 2.859 7.88 3.101 ;
  LAYER met2 ;
        RECT 7.74 2.8 8.17 3.08 ;
  LAYER met2 ;
        RECT 5.43 10.36 5.75 10.64 ;
  LAYER met3 ;
        RECT 5.45 10.34 5.73 10.66 ;
  LAYER met2 ;
        RECT 7.58 2.8 7.9 3.08 ;
  LAYER met3 ;
        RECT 7.6 2.78 7.88 3.1 ;
  LAYER met2 ;
        RECT 5.43 10.36 5.75 10.64 ;
  LAYER met3 ;
        RECT 5.45 10.34 5.73 10.66 ;
  LAYER met3 ;
        RECT 7.6 2.835 7.88 3.205 ;
  LAYER met4 ;
        RECT 7.575 2.62 7.905 3.42 ;
  LAYER met3 ;
        RECT 5.45 2.835 5.73 3.205 ;
  LAYER met4 ;
        RECT 5.425 2.62 5.755 3.42 ;
  LAYER met2 ;
        RECT 5.43 10.36 5.75 10.64 ;
  LAYER met3 ;
        RECT 5.45 10.34 5.73 10.66 ;
  LAYER met3 ;
        RECT 5.45 2.835 5.73 3.205 ;
  LAYER met4 ;
        RECT 5.425 2.62 5.755 3.42 ;
  LAYER met3 ;
        RECT 5.02 2.36 5.3 6.88 ;
  LAYER met2 ;
        RECT 4.56 9.94 5.76 10.22 ;
  LAYER met2 ;
        RECT 1.12 2.8 2.32 3.08 ;
  LAYER met3 ;
        RECT 5.02 6.135 5.3 6.505 ;
  LAYER met4 ;
        RECT 4.4 5.92 5.16 6.72 ;
  LAYER met5 ;
        RECT 3.81 6.32 4.99 9.62 ;
  LAYER met4 ;
        RECT 4.4 9.22 4.73 10.02 ;
  LAYER met3 ;
        RECT 4.59 9.62 4.87 10.08 ;
  LAYER met2 ;
        RECT 4.57 9.94 4.89 10.22 ;
  LAYER met3 ;
        RECT 5.02 3.175 5.3 3.545 ;
  LAYER met2 ;
        RECT 2.58 3.22 5.16 3.5 ;
  LAYER met1 ;
        RECT 2.455 2.94 2.705 3.36 ;
  LAYER met2 ;
        RECT 2.15 2.8 2.58 3.08 ;
  LAYER met2 ;
        RECT 4.57 9.94 4.89 10.22 ;
  LAYER met3 ;
        RECT 4.59 9.92 4.87 10.24 ;
  LAYER met3 ;
        RECT 5.02 6.135 5.3 6.505 ;
  LAYER met4 ;
        RECT 4.995 5.92 5.325 6.72 ;
  LAYER met3 ;
        RECT 4.59 9.435 4.87 9.805 ;
  LAYER met4 ;
        RECT 4.565 9.22 4.895 10.02 ;
  LAYER met4 ;
        RECT 4.235 9.22 4.565 10.02 ;
  LAYER met5 ;
        RECT 3.81 9.455 4.99 9.785 ;
  LAYER met4 ;
        RECT 4.235 5.92 4.565 6.72 ;
  LAYER met5 ;
        RECT 3.81 6.155 4.99 6.485 ;
  LAYER met1 ;
        RECT 2.455 3.275 2.705 3.445 ;
  LAYER met2 ;
        RECT 2.41 3.22 2.75 3.5 ;
  LAYER met1 ;
        RECT 2.455 2.855 2.705 3.025 ;
  LAYER met2 ;
        RECT 2.41 2.8 2.75 3.08 ;
  LAYER met2 ;
        RECT 5 3.22 5.32 3.5 ;
  LAYER met3 ;
        RECT 5.02 3.2 5.3 3.52 ;
  LAYER met2 ;
        RECT 4.57 9.94 4.89 10.22 ;
  LAYER met3 ;
        RECT 4.59 9.92 4.87 10.24 ;
  LAYER met3 ;
        RECT 5.02 6.135 5.3 6.505 ;
  LAYER met4 ;
        RECT 4.995 5.92 5.325 6.72 ;
  LAYER met3 ;
        RECT 4.59 9.435 4.87 9.805 ;
  LAYER met4 ;
        RECT 4.565 9.22 4.895 10.02 ;
  LAYER met4 ;
        RECT 4.235 9.22 4.565 10.02 ;
  LAYER met5 ;
        RECT 3.81 9.455 4.99 9.785 ;
  LAYER met4 ;
        RECT 4.235 5.92 4.565 6.72 ;
  LAYER met5 ;
        RECT 3.81 6.155 4.99 6.485 ;
  LAYER met1 ;
        RECT 2.455 3.275 2.705 3.445 ;
  LAYER met2 ;
        RECT 2.41 3.22 2.75 3.5 ;
  LAYER met1 ;
        RECT 2.455 2.855 2.705 3.025 ;
  LAYER met2 ;
        RECT 2.41 2.8 2.75 3.08 ;
  LAYER met2 ;
        RECT 5 3.22 5.32 3.5 ;
  LAYER met3 ;
        RECT 5.02 3.2 5.3 3.52 ;
  LAYER met2 ;
        RECT 4.57 9.94 4.89 10.22 ;
  LAYER met3 ;
        RECT 4.59 9.92 4.87 10.24 ;
  LAYER met3 ;
        RECT 5.02 6.135 5.3 6.505 ;
  LAYER met4 ;
        RECT 4.995 5.92 5.325 6.72 ;
  LAYER met3 ;
        RECT 4.59 9.435 4.87 9.805 ;
  LAYER met4 ;
        RECT 4.565 9.22 4.895 10.02 ;
  LAYER met4 ;
        RECT 4.235 9.22 4.565 10.02 ;
  LAYER met5 ;
        RECT 3.81 9.455 4.99 9.785 ;
  LAYER met4 ;
        RECT 4.235 5.92 4.565 6.72 ;
  LAYER met5 ;
        RECT 3.81 6.155 4.99 6.485 ;
  LAYER met1 ;
        RECT 5.465 3.695 5.715 7.225 ;
  LAYER met1 ;
        RECT 5.465 2.435 5.715 3.445 ;
  LAYER met1 ;
        RECT 5.465 0.335 5.715 1.345 ;
  LAYER met1 ;
        RECT 5.895 3.695 6.145 7.225 ;
  LAYER met1 ;
        RECT 5.035 3.695 5.285 7.225 ;
  LAYER met1 ;
        RECT 4.605 3.695 4.855 7.225 ;
  LAYER met1 ;
        RECT 4.605 2.435 4.855 3.445 ;
  LAYER met1 ;
        RECT 4.605 0.335 4.855 1.345 ;
  LAYER met1 ;
        RECT 4.175 3.695 4.425 7.225 ;
  LAYER met2 ;
        RECT 4.56 2.8 5.76 3.08 ;
  LAYER met2 ;
        RECT 5.42 7 6.62 7.28 ;
  LAYER met2 ;
        RECT 4.99 2.38 6.19 2.66 ;
  LAYER met2 ;
        RECT 4.56 6.58 5.76 6.86 ;
  LAYER met2 ;
        RECT 4.56 0.7 5.76 0.98 ;
  LAYER met3 ;
        RECT 5.45 2.78 5.73 7.3 ;
  LAYER met3 ;
        RECT 5.02 2.36 5.3 6.88 ;
  LAYER met2 ;
        RECT 4.13 6.16 6.19 6.44 ;
  LAYER met1 ;
        RECT 6.325 11.255 6.575 14.785 ;
  LAYER met1 ;
        RECT 6.325 9.995 6.575 11.005 ;
  LAYER met1 ;
        RECT 6.325 7.895 6.575 8.905 ;
  LAYER met1 ;
        RECT 6.755 11.255 7.005 14.785 ;
  LAYER met1 ;
        RECT 5.895 11.255 6.145 14.785 ;
  LAYER met1 ;
        RECT 5.465 11.255 5.715 14.785 ;
  LAYER met1 ;
        RECT 5.465 9.995 5.715 11.005 ;
  LAYER met1 ;
        RECT 5.465 7.895 5.715 8.905 ;
  LAYER met1 ;
        RECT 5.035 11.255 5.285 14.785 ;
  LAYER met1 ;
        RECT 4.605 11.255 4.855 14.785 ;
  LAYER met1 ;
        RECT 4.605 9.995 4.855 11.005 ;
  LAYER met1 ;
        RECT 4.605 7.895 4.855 8.905 ;
  LAYER met1 ;
        RECT 4.175 11.255 4.425 14.785 ;
  LAYER met1 ;
        RECT 3.745 11.255 3.995 14.785 ;
  LAYER met1 ;
        RECT 3.745 9.995 3.995 11.005 ;
  LAYER met1 ;
        RECT 3.745 7.895 3.995 8.905 ;
  LAYER met1 ;
        RECT 3.315 11.255 3.565 14.785 ;
  LAYER met2 ;
        RECT 3.7 8.26 6.62 8.54 ;
  LAYER met2 ;
        RECT 3.7 14.56 6.62 14.84 ;
  LAYER met2 ;
        RECT 4.56 14.14 5.76 14.42 ;
  LAYER met2 ;
        RECT 3.7 10.36 6.62 10.64 ;
  LAYER met2 ;
        RECT 4.56 9.94 5.76 10.22 ;
  LAYER met2 ;
        RECT 3.27 13.72 7.05 14 ;
  LAYER met1 ;
        RECT 8.905 3.695 9.155 7.225 ;
  LAYER met1 ;
        RECT 8.905 2.435 9.155 3.445 ;
  LAYER met1 ;
        RECT 8.905 0.335 9.155 1.345 ;
  LAYER met1 ;
        RECT 9.335 3.695 9.585 7.225 ;
  LAYER met1 ;
        RECT 8.475 3.695 8.725 7.225 ;
  LAYER met1 ;
        RECT 8.045 3.695 8.295 7.225 ;
  LAYER met1 ;
        RECT 8.045 2.435 8.295 3.445 ;
  LAYER met1 ;
        RECT 8.045 0.335 8.295 1.345 ;
  LAYER met1 ;
        RECT 7.615 3.695 7.865 7.225 ;
  LAYER met2 ;
        RECT 8 0.7 9.2 0.98 ;
  LAYER met2 ;
        RECT 8 7 9.2 7.28 ;
  LAYER met2 ;
        RECT 7.57 6.58 9.63 6.86 ;
  LAYER met2 ;
        RECT 8 2.8 9.2 3.08 ;
  LAYER met3 ;
        RECT 8.03 0.68 8.31 7.3 ;
  LAYER met1 ;
        RECT 1.165 3.695 1.415 7.225 ;
  LAYER met1 ;
        RECT 1.165 2.435 1.415 3.445 ;
  LAYER met1 ;
        RECT 1.165 0.335 1.415 1.345 ;
  LAYER met1 ;
        RECT 0.735 3.695 0.985 7.225 ;
  LAYER met1 ;
        RECT 1.595 3.695 1.845 7.225 ;
  LAYER met1 ;
        RECT 2.025 3.695 2.275 7.225 ;
  LAYER met1 ;
        RECT 2.025 2.435 2.275 3.445 ;
  LAYER met1 ;
        RECT 2.025 0.335 2.275 1.345 ;
  LAYER met1 ;
        RECT 2.455 3.695 2.705 7.225 ;
  LAYER met2 ;
        RECT 1.12 0.7 2.32 0.98 ;
  LAYER met2 ;
        RECT 1.12 7 2.32 7.28 ;
  LAYER met2 ;
        RECT 0.69 6.58 2.75 6.86 ;
  LAYER met2 ;
        RECT 1.12 2.8 2.32 3.08 ;
  LAYER met3 ;
        RECT 2.01 0.68 2.29 7.3 ;
  END
END DCDC_CONV2TO1
